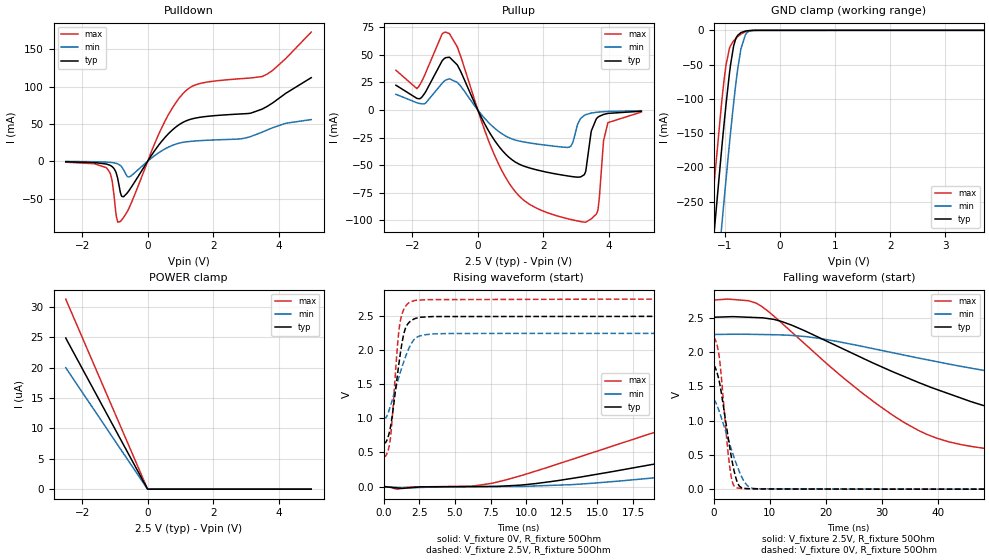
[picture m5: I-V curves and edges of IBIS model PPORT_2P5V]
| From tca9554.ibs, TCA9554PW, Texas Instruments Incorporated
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[Model]   PPORT_2P5V
Model_type   I/O
Polarity   Non-Inverting
Enable   Active-Low
Vinl = .8
Vinh = 2
Vmeas = 1.25
Vref = 2.5
Cref = 15pF
Rref = 50
|   typ   min   max
C_comp   2.511p   2.431p   2.702p
|C_comp (ON state)   2.696p   2.553p   2.895p
|C_comp (OFF state)   2.511p   2.431p   2.702p
[Voltage Range]   2.5   2.25   2.75
[Temperature Range]   27   125   -40
[Pullup Reference]   2.5   2.25   2.75
[Pulldown Reference]   -0   -0   -0
[Power Clamp Reference]   2.5   2.25   2.75
[GND Clamp Reference]   -0   -0   -0
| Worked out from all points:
|   slope of the pulldown table from 0 to 0.375 V, typ, clamps not added: 15.8 ohm
|   slope of the pullup table from 0 to 0.375 V, typ, clamps not added: 17.7 ohm
|   GND clamp passes 1 mA (typ) near -0.62 V on its own axis
|   falling waveform, V_fixture 2.5V, R_fixture 50Ohm: 20-80 % time 36.6ns typ, 66ns min, 21.5ns max; typ from 2.5 V to 0.641 V
|   rising waveform, V_fixture 0V, R_fixture 50Ohm: 20-80 % time 38.7ns typ, 55.5ns min, 23.9ns max; typ from 0 V to 1.78 V
|   rising waveform, V_fixture 2.5V, R_fixture 50Ohm: 20-80 % time 721ps typ, 1.14ns min, 508ps max; typ from 0.641 V to 2.5 V
|   falling waveform, V_fixture 0V, R_fixture 50Ohm: 20-80 % time 2.09ns typ, 3.14ns min, 1.46ns max; typ from 1.78 V to 0 V
[Pulldown]
|   Voltage   I(typ)   I(min)   I(max)
-2.5V     -772.7uA   -289.8uA   -1.301mA
-1.248V   -3.942mA   -1.222mA   -9.316mA
-1.09V    -7.071mA   -1.833mA   -25.27mA
-977.5mV  -13.87mA   -2.72mA    -67.17mA
-917.5mV  -22.82mA   -3.556mA   -81.19mA
-835mV    -41.68mA   -5.666mA   -80.78mA
-572.5mV  -39.52mA   -21.16mA   -63.16mA
410mV     25.73mA    13.44mA    43.17mA
1.085V    52.28mA    25.36mA    90.98mA
1.685V    59.44mA    27.8mA     105.1mA
3.493V    69.81mA    38.9mA     113.5mA
4.992V    112mA      55.82mA    173.1mA
[GND Clamp]
|   Voltage   I(typ)   I(min)   I(max)
-2.5V     -1.557A    -1.668A    -1.488A
-1.278V   -372.4mA   -488.5mA   -299.8mA
-1.21V    -310mA     -425.9mA   -237.7mA
-1.052V   -169.6mA   -283mA     -102mA
-977.5mV  -107.9mA   -217.5mA   -50.55mA
-917.5mV  -64.21mA   -167.1mA   -26.76mA
-842.5mV  -24.21mA   -108.2mA   -15.8mA
-767.5mV  -7.428mA   -57.35mA   -9.452mA
-707.5mV  -3.349mA   -27.12mA   -5.491mA
-617.5mV  -987.2uA   -5.331mA   -1.677mA
-475mV    -96.96uA   -209.9uA   -125.3uA
4.992V    0A         0A         0A
[Pullup]
|   Voltage   I(typ)   I(min)   I(max)
-2.5V     22.44mA    14.24mA    35.99mA
-1.855V   10.51mA    6.508mA    19.54mA
-1.09V    44.48mA    24.16mA    68.86mA
-865mV    47.8mA     28.28mA    69.16mA
1.025V    -44.64mA   -26.02mA   -69.28mA
2.788V    -59.91mA   -33.71mA   -98.78mA
3.147V    -60.51mA   -7.419mA   -101.1mA
3.29V     -55.88mA   -4.304mA   -101.6mA
3.658V    -6.767mA   -1.96mA    -91.59mA
3.837V    -4.033mA   -1.535mA   -27.9mA
3.973V    -3.071mA   -1.319mA   -11.45mA
4.992V    -1.073mA   -633.1uA   -1.823mA
[POWER Clamp]
|   Voltage   I(typ)   I(min)   I(max)
-2.5V     24.9uA     20.02uA    31.31uA
-10mV     60.17nA    42.85nA    86.31nA
5mV       0A         0A         0A
4.992V    0A         0A         0A
[Ramp]
R_load = 50
|   typ   min   max
dV/dt_r   1.06955/3.85271e-08   0.769104/5.55669e-08   1.31721/2.38503e-08
dV/dt_f   1.11535/3.65108e-08   0.746971/6.60089e-08   1.3844/2.14496e-08
[Falling Waveform]
V_fixture = 2.5V
V_fixture_min = 2.25V
V_fixture_max = 2.75V
R_fixture = 50Ohm
C_fixture = 0F
|   Time   V(typ)   V(min)   V(max)
0s        2.5V       2.25V      2.75V
8.572ns   2.497V     2.253V     2.66V
13.86ns   2.39V      2.24V      2.291V
25.89ns   1.933V     2.089V     1.436V
36.63ns   1.549V     1.907V     848.1mV
45.97ns   1.271V     1.761V     621.1mV
59.14ns   984.1mV    1.583V     520.6mV
85.7ns    744.8mV    1.327V     465.5mV
152.3ns   651.9mV    1.077V     446.6mV
499.9ns   641.1mV    1.005V     442.7mV
[Rising Waveform]
V_fixture = 0V
V_fixture_min = 0V
V_fixture_max = 0V
R_fixture = 50Ohm
C_fixture = 0F
|   Time   V(typ)   V(min)   V(max)
0s        257.2uV    48.96nV    223.7uV
7.59ns    1.721mV    34.56uV    47.93mV
12.07ns   82.7mV     20.04mV    320.6mV
25.54ns   574mV      263.5mV    1.198V
37.99ns   979.1mV    508mV      1.768V
48.06ns   1.233V     672.8mV    1.994V
64.71ns   1.516V     884.6mV    2.118V
100.7ns   1.718V     1.135V     2.178V
152.3ns   1.769V     1.246V     2.192V
499.9ns   1.783V     1.282V     2.196V
[Rising Waveform]
V_fixture = 2.5V
V_fixture_min = 2.25V
V_fixture_max = 2.75V
R_fixture = 50Ohm
C_fixture = 0F
|   Time   V(typ)   V(min)   V(max)
0s        641.1mV    1.005V     442.7mV
266.4ps   701.5mV    1.054V     502.2mV
480.5ps   874.4mV    1.186V     715.9mV
988.3ps   1.67V      1.546V     2.11V
1.246ns   2.052V     1.725V     2.5V
1.431ns   2.255V     1.843V     2.605V
1.692ns   2.385V     1.989V     2.682V
2.241ns   2.467V     2.178V     2.731V
2.964ns   2.488V     2.228V     2.741V
499.9ns   2.5V       2.25V      2.75V
[Falling Waveform]
|Gnd
V_fixture = 0V
V_fixture_min = 0V
V_fixture_max = 0V
R_fixture = 50Ohm
C_fixture = 0F
|   Time   V(typ)   V(min)   V(max)
0s        1.783V     1.282V     2.196V
546.8ps   1.707V     1.227V     2.111V
1.039ns   1.546V     1.118V     1.889V
2.491ns   790.8mV    745.6mV    575.4mV
3.139ns   465.2mV    578.2mV    165.1mV
4.128ns   113.9mV    345.9mV    19.75mV
5.306ns   13.7mV     128.2mV    7.235mV
6.518ns   6.354mV    21.75mV    5.692mV
8.675ns   3.679mV    4.234mV    5.158mV
499.9ns   257.2uV    84.24nV    223.7uV
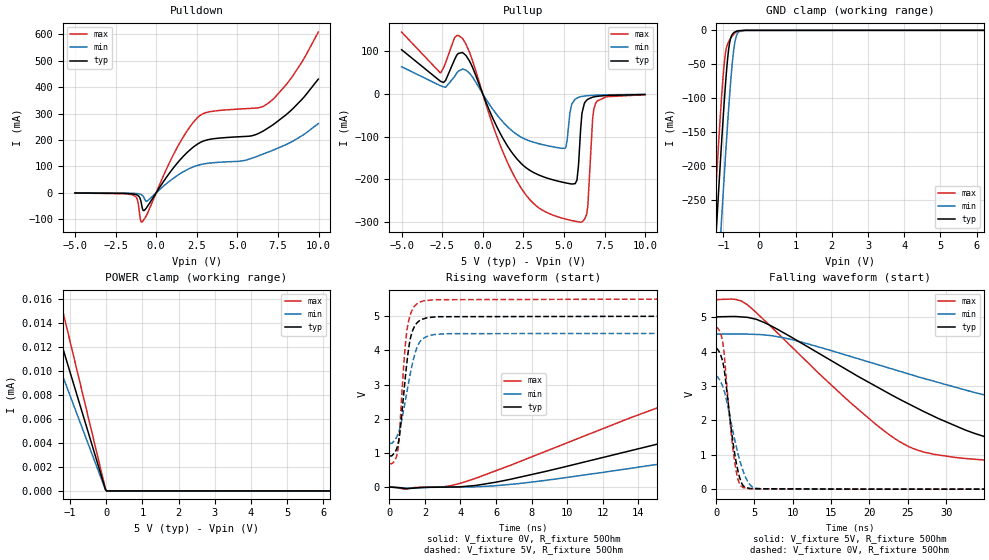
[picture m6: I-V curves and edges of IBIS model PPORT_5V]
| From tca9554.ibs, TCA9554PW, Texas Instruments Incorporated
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[Model]   PPORT_5V
Model_type   I/O
Polarity   Non-Inverting
Enable   Active-Low
Vinl = .8
Vinh = 2
Vmeas = 2.5
Vref = 5
Cref = 15pF
Rref = 50
|   typ   min   max
C_comp   2.446p   2.284p   2.721p
|C_comp (ON state)   2.718p   2.500p   2.993p
|C_comp (OFF state)   2.446p   2.284p   2.721p
[Voltage Range]   5   4.5   5.5
[Temperature Range]   27   125   -40
[Pullup Reference]   5   4.5   5.5
[Pulldown Reference]   -0   -0   -0
[Power Clamp Reference]   5   4.5   5.5
[GND Clamp Reference]   -0   -0   -0
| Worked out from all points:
|   slope of the pulldown table from 0 to 0.75 V, typ, clamps not added: 10.9 ohm
|   slope of the pullup table from 0 to 0.75 V, typ, clamps not added: 11.1 ohm
|   GND clamp passes 1 mA (typ) near -0.62 V on its own axis
|   POWER clamp passes 1 mA (typ) near -3.03 V on its own axis
|   falling waveform, V_fixture 5V, R_fixture 50Ohm: 20-80 % time 20.8ns typ, 34.9ns min, 14.2ns max; typ from 5 V to 0.908 V
|   rising waveform, V_fixture 0V, R_fixture 50Ohm: 20-80 % time 22.9ns typ, 33.1ns min, 15.5ns max; typ from 0 V to 4.08 V
|   rising waveform, V_fixture 5V, R_fixture 50Ohm: 20-80 % time 503ps typ, 732ps min, 403ps max; typ from 0.908 V to 5 V
|   falling waveform, V_fixture 0V, R_fixture 50Ohm: 20-80 % time 1.4ns typ, 2ns min, 1.2ns max; typ from 4.08 V to 0 V
[Pulldown]
|   Voltage   I(typ)   I(min)   I(max)
-5V       -470.9uA   -234.2uA   -696.9uA
-1.475V   -3.768mA   -1.595mA   -7.023mA
-1.175V   -8.101mA   -2.788mA   -22.63mA
-950mV    -28.84mA   -5.672mA   -105.9mA
-875mV    -51.19mA   -8.117mA   -110.4mA
-560mV    -53.43mA   -31.26mA   -80.73mA
1.06V     94.1mA     55.1mA     144mA
2.53V     183.8mA    103.4mA    283.4mA
5.89V     215.7mA    130.7mA    319.7mA
7.015V    250mA      156.8mA    344mA
8.425V    318.6mA    195.6mA    443.3mA
9.985V    430.1mA    261.9mA    608mA
[GND Clamp]
|   Voltage   I(typ)   I(min)   I(max)
-5V       -4.032A    -4.137A    -3.968A
-1.43V    -516mA     -631.9mA   -443.5mA
-1.25V    -346.9mA   -462.9mA   -274.4mA
-1.145V   -250.9mA   -366.2mA   -179.5mA
-1.055V   -171.7mA   -285.2mA   -104mA
-950mV    -87.04mA   -194.1mA   -37.25mA
-845mV    -25.17mA   -110mA     -16.06mA
-740mV    -5.093mA   -42.03mA   -7.532mA
-695mV    -2.879mA   -22.43mA   -4.822mA
-635mV    -1.3mA     -7.644mA   -2.23mA
-410mV    -69.21uA   -80.31uA   -90.56uA
9.985V    0A         0A         0A
[Pullup]
|   Voltage   I(typ)   I(min)   I(max)
-5V       103.8mA    63.81mA    145.2mA
-2.615V   29.92mA    19.38mA    49.38mA
-1.25V    97.23mA    58.52mA    130.6mA
2.11V     -152.9mA   -95.52mA   -205.1mA
5.095V    -208.8mA   -126.1mA   -293.7mA
5.47V     -211.5mA   -25.43mA   -297.1mA
5.8V      -202.1mA   -9.643mA   -299.8mA
6.1V      -48.57mA   -6.016mA   -300.7mA
6.4V      -14.63mA   -4.347mA   -282mA
6.76V     -7.71mA    -3.253mA   -61.27mA
6.955V    -6.119mA   -2.86mA    -21.71mA
9.985V    -1.434mA   -987.9uA   -1.885mA
[POWER Clamp]
|   Voltage   I(typ)   I(min)   I(max)
-5V       3.194mA    3.279mA    4.398mA
-2.015V   23.43uA    16.2uA     246.9uA
-1.775V   17.61uA    14.15uA    25.44uA
-1.25V    12.38uA    9.943uA    15.58uA
-20mV     125nA      90.63nA    177.2nA
10mV      0A         0A         0A
9.985V    0A         0A         0A
[Ramp]
R_load = 50
|   typ   min   max
dV/dt_r   2.44602/2.29005e-08   1.96118/3.29329e-08   2.8142/1.55072e-08
dV/dt_f   2.4554/2.07876e-08   1.93407/3.4785e-08   2.88977/1.41631e-08
[Falling Waveform]
V_fixture = 5V
V_fixture_min = 4.5V
V_fixture_max = 5.5V
R_fixture = 50Ohm
C_fixture = 0F
|   Time   V(typ)   V(min)   V(max)
0s        5V         4.5V       5.5V
4.034ns   5V         4.511V     5.371V
9.858ns   4.417V     4.351V     4.141V
23.4ns    2.679V     3.467V     1.458V
31.09ns   1.856V     2.974V     925.5mV
37.67ns   1.383V     2.595V     816.1mV
44.47ns   1.183V     2.251V     765mV
56.56ns   1.044V     1.792V     725.5mV
72.13ns   973.3mV    1.529V     704.1mV
199.9ns   907.7mV    1.277V     683.7mV
[Rising Waveform]
V_fixture = 0V
V_fixture_min = 0V
V_fixture_max = 0V
R_fixture = 50Ohm
C_fixture = 0F
|   Time   V(typ)   V(min)   V(max)
0s        382uV      434.3uV    347uV
4.034ns   8.027mV    358.4uV    117mV
16.78ns   1.472V     792.4mV    2.642V
23.59ns   2.267V     1.305V     3.728V
28.44ns   2.756V     1.634V     4.195V
34.09ns   3.231V     1.977V     4.415V
42ns      3.631V     2.38V      4.54V
53.61ns   3.85V      2.79V      4.618V
77.61ns   4.003V     3.105V     4.668V
199.9ns   4.077V     3.269V     4.691V
[Rising Waveform]
V_fixture = 5V
V_fixture_min = 4.5V
V_fixture_max = 5.5V
R_fixture = 50Ohm
C_fixture = 0F
|   Time   V(typ)   V(min)   V(max)
0s        907.7mV    1.277V     683.7mV
330.5ps   1.033V     1.397V     800.7mV
487.5ps   1.269V     1.556V     1.133V
642.4ps   1.837V     1.836V     2.225V
885ps     3.159V     2.492V     4.099V
1.134ns   4.222V     3.21V      4.969V
1.313ns   4.588V     3.653V     5.209V
1.631ns   4.844V     4.18V      5.394V
2.499ns   4.974V     4.459V     5.48V
199.9ns   5V         4.5V       5.5V
[Falling Waveform]
|Gnd
V_fixture = 0V
V_fixture_min = 0V
V_fixture_max = 0V
R_fixture = 50Ohm
C_fixture = 0F
|   Time   V(typ)   V(min)   V(max)
0s        4.077V     3.269V     4.691V
532.5ps   3.939V     3.154V     4.562V
923.6ps   3.648V     2.95V      4.195V
2.037ns   1.647V     1.855V     1.481V
2.672ns   721mV      1.197V     466.4mV
3.314ns   186.8mV    665.4mV    81.86mV
4.034ns   36.25mV    264.9mV    20.09mV
4.711ns   13.97mV    68.85mV    14.32mV
6.217ns   10.83mV    9.217mV    12.19mV
199.9ns   382uV      434.3uV    347uV
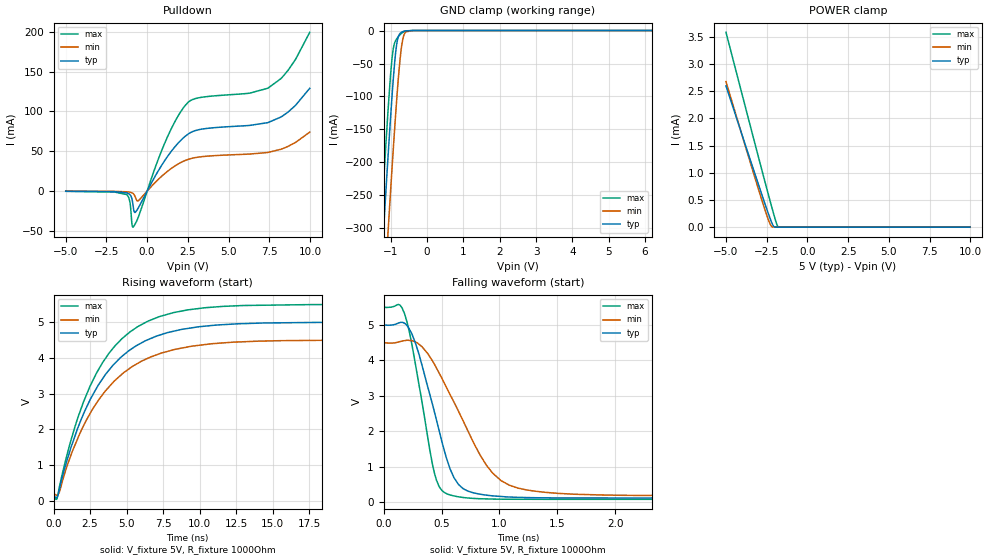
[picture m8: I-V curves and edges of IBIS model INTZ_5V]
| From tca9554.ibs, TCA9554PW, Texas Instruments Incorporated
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[Model]   INTZ_5V
Model_type   Open_drain
Polarity   Non-Inverting
Vmeas = 2.5
Vref = 5
Cref = 15pF
Rref = 1000
|   typ   min   max
|   (nom PVT)   (slow PVT)   (fast PVT)
C_comp   1.553p   1.445p   1.692p
|C_comp (ON state)   1.553p   1.445p   1.692p
|C_comp (OFF state)   1.553p   1.420p   1.831p
| Where   nom PVT is  Nominal Process, 5.0V, 27C
|   Fast PVT is Strong Process, 5.5V, -40C
|   Slow PVT is Weak Process, 4.5V, 125C
[Voltage Range]   5   4.5   5.5
[Temperature Range]   27   125   -40
[Pullup Reference]   5   4.5   5.5
[Pulldown Reference]   -0   -0   -0
[Power Clamp Reference]   5   4.5   5.5
[GND Clamp Reference]   -0   -0   -0
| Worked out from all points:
|   slope of the pulldown table from 0 to 0.75 V, typ, clamps not added: 27.1 ohm
|   GND clamp passes 1 mA (typ) near -0.64 V on its own axis
|   POWER clamp passes 1 mA (typ) near -3.25 V on its own axis
|   falling waveform, V_fixture 5V, R_fixture 1000Ohm: 20-80 % time 240ps typ, 407ps min, 170ps max; typ from 5 V to 0.119 V
|   rising waveform, V_fixture 5V, R_fixture 1000Ohm: 20-80 % time 3.72ns typ, 3.98ns min, 3.54ns max; typ from 0.119 V to 5 V
[Pulldown]
|   Voltage   I(typ)   I(min)   I(max)
-5V       -178uA     -88.8uA    -261.6uA
-1.25V    -2.202mA   -867.5uA   -4.422mA
-1.055V   -4.475mA   -1.4mA     -13.89mA
-935mV    -9.706mA   -2.15mA    -41.06mA
-860mV    -18.62mA   -3.086mA   -45.09mA
-755mV    -26.85mA   -6.098mA   -41.89mA
-545mV    -21.11mA   -12.16mA   -32.86mA
1.06V     37.74mA    21.65mA    59.26mA
2.32V     68.51mA    38.3mA     107.2mA
7.42V     86mA       48.51mA    129.2mA
8.65V     99.16mA    56.11mA    151.5mA
9.985V    129mA      74.01mA    199.3mA
[GND Clamp]
|   Voltage   I(typ)   I(min)   I(max)
-5V       -4.031A    -4.136A    -3.967A
-1.43V    -515.4mA   -631.3mA   -442.8mA
-1.25V    -346.1mA   -462.2mA   -273.4mA
-1.145V   -249.9mA   -365.4mA   -178.2mA
-1.1V     -209.7mA   -324.5mA   -139.1mA
-1.055V   -170.4mA   -284.2mA   -101.9mA
-965mV    -96.49mA   -205.5mA   -40.48mA
-860mV    -28.9mA    -119.7mA   -14.37mA
-755mV    -4.911mA   -47.79mA   -6.833mA
-665mV    -1.479mA   -11.43mA   -2.606mA
-410mV    -11.62uA   -28.96uA   -12.78uA
9.985V    0A         0A         0A
[POWER Clamp]
|   Voltage   I(typ)   I(min)   I(max)
-5V       2.598mA    2.677mA    3.583mA
-3.155V   918.1uA    843.2uA    1.46mA
-2.435V   281.1uA    168.2uA    642uA
-2.255V   132.7uA    37.62uA    441.6uA
-2.18V    76.52uA    9.466uA    359.2uA
-2.09V    22.54uA    855.7nA    262uA
-1.91V    18.29nA    0A         80.42uA
-1.805V   0A         0A         9.126uA
9.985V    0A         0A         0A
[Ramp]
R_load = 1000
|   typ   min   max
dV/dt_r   2.92861/3.72406e-09   2.58856/3.98229e-09   3.25108/3.53979e-09
dV/dt_f   2.92861/2.39968e-10   2.58857/4.06892e-10   3.25108/1.70249e-10
[Falling Waveform]
V_fixture = 5V
V_fixture_min = 4.5V
V_fixture_max = 5.5V
R_fixture = 1000Ohm
C_fixture = 0F
|   Time   V(typ)   V(min)   V(max)
0s        5V         4.5V       5.5V
180.7ps   5.046V     4.557V     5.314V
275.6ps   4.48V      4.516V     3.87V
422.3ps   2.754V     3.981V     1.058V
479.1ps   2.021V     3.642V     442.4mV
647.1ps   496.2mV    2.56V      152.5mV
958.9ps   175.5mV    769.6mV    87.48mV
1.393ns   124.2mV    279.8mV    82.15mV
3.042ns   119.1mV    185.8mV    81.65mV
99.9ns    119mV      185.7mV    81.53mV
[Rising Waveform]
V_fixture = 5V
V_fixture_min = 4.5V
V_fixture_max = 5.5V
R_fixture = 1000Ohm
C_fixture = 0F
|   Time   V(typ)   V(min)   V(max)
0s        119mV      185.7mV    81.53mV
245.3ps   89.35mV    154.6mV    65.2mV
1.052ns   1.302V     1.118V     1.485V
2.037ns   2.415V     2.084V     2.751V
2.922ns   3.137V     2.722V     3.561V
3.808ns   3.665V     3.193V     4.138V
5.773ns   4.367V     3.851V     4.88V
9.192ns   4.828V     4.31V      5.349V
18.97ns   4.997V     4.497V     5.497V
99.9ns    5V         4.5V       5.5V
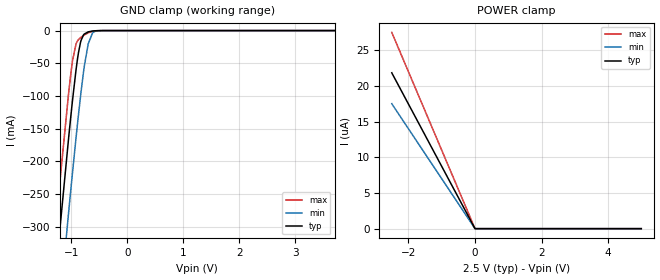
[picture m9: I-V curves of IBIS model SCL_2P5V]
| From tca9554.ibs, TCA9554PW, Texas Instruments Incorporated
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[Model]   SCL_2P5V
Model_type   Input
Vinl = .8
Vinh = 2
|   typ   min   max
|   (nom PVT)   (slow PVT)   (fast PVT)
C_comp   1.373p   1.325p   1.458p
| Where   nom PVT is  Nominal Process, 2.5V, 27C
|   Fast PVT is Strong Process, 2.75V, -40C
|   Slow PVT is Weak Process, 2.25V, 125C
[Voltage Range]   2.5   2.25   2.75
[Temperature Range]   27   125   -40
[Power Clamp Reference]   2.5   2.25   2.75
[GND Clamp Reference]   -0   -0   -0
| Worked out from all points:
|   GND clamp passes 1 mA (typ) near -0.64 V on its own axis
[GND Clamp]
|   Voltage   I(typ)   I(min)   I(max)
-2.5V     -1.556A    -1.668A    -1.487A
-1.48V    -562.8mA   -678.5mA   -490.3mA
-1.27V    -364.2mA   -480.4mA   -291.4mA
-1.218V   -315.6mA   -431.6mA   -242.9mA
-1.052V   -167.5mA   -281.4mA   -98.76mA
-977.5mV  -105.3mA   -215.6mA   -45.46mA
-917.5mV  -60.82mA   -164.9mA   -20.68mA
-835mV    -17.56mA   -99.86mA   -10.75mA
-700mV    -2.039mA   -20.57mA   -3.478mA
-625mV    -712.5uA   -4.147mA   -1.247mA
-490mV    -63.51uA   -156.7uA   -84.56uA
4.992V    0A         0A         0A
[POWER Clamp]
|   Voltage   I(typ)   I(min)   I(max)
-2.5V     21.83uA    17.51uA    27.48uA
-145mV    1.247uA    997.2nA    1.576uA
-2.5mV    3.204nA    26.14nA    9.732nA
4.992V    0A         0A         0A
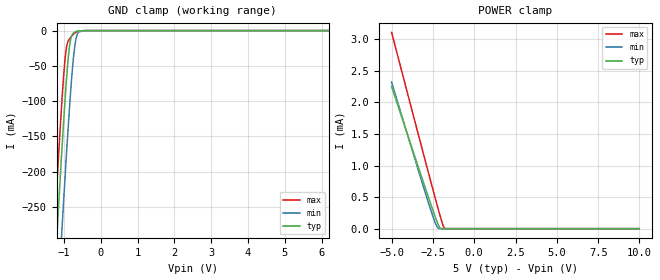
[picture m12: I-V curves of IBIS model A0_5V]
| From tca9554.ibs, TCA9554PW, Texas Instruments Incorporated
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[Model]   A0_5V
Model_type   Input
Vinl = .8
Vinh = 2
|   typ   min   max
|   (nom PVT)   (slow PVT)   (fast PVT)
C_comp   1.351p   1.281p   1.458p
| Where   nom PVT is  Nominal Process, 5.0V, 27C
|   Fast PVT is Strong Process, 5.5V, -40C
|   Slow PVT is Weak Process, 4.5V, 125C
[Voltage Range]   5   4.5   5.5
[Temperature Range]   27   125   -40
[Power Clamp Reference]   5   4.5   5.5
[GND Clamp Reference]   -0   -0   -0
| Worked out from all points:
|   GND clamp passes 1 mA (typ) near -0.65 V on its own axis
|   POWER clamp passes 1 mA (typ) near -3.41 V on its own axis
[GND Clamp]
|   Voltage   I(typ)   I(min)   I(max)
-5V       -4.031A    -4.136A    -3.967A
-1.43V    -515.1mA   -631mA     -442.5mA
-1.25V    -345.6mA   -461.8mA   -272.8mA
-1.145V   -249.3mA   -364.9mA   -177.4mA
-1.055V   -169.7mA   -283.6mA   -100.8mA
-950mV    -84.07mA   -192.1mA   -31.42mA
-845mV    -21.12mA   -107.3mA   -11.47mA
-740mV    -3.443mA   -38.39mA   -5.223mA
-665mV    -1.274mA   -10.35mA   -2.256mA
-590mV    -399uA     -1.762mA   -669.1uA
-425mV    -14.09uA   -33.8uA    -16.34uA
9.985V    0A         0A         0A
[POWER Clamp]
|   Voltage   I(typ)   I(min)   I(max)
-5V       2.256mA    2.324mA    3.111mA
-3.155V   797.2uA    732.2uA    1.267mA
-2.435V   244uA      146.1uA    557.4uA
-2.255V   115.2uA    32.66uA    383.4uA
-2.18V    66.43uA    8.215uA    311.9uA
-2.09V    19.56uA    740.1nA    227.5uA
-1.91V    12.4nA     0A         69.82uA
-1.805V   0A         0A         7.919uA
9.985V    0A         0A         0A
